VERSION 5.8 ;
BUSBITCHARS "[]" ;
DIVIDERCHAR "/" ;
UNITS
    DATABASE MICRONS 1000 ;
END UNITS

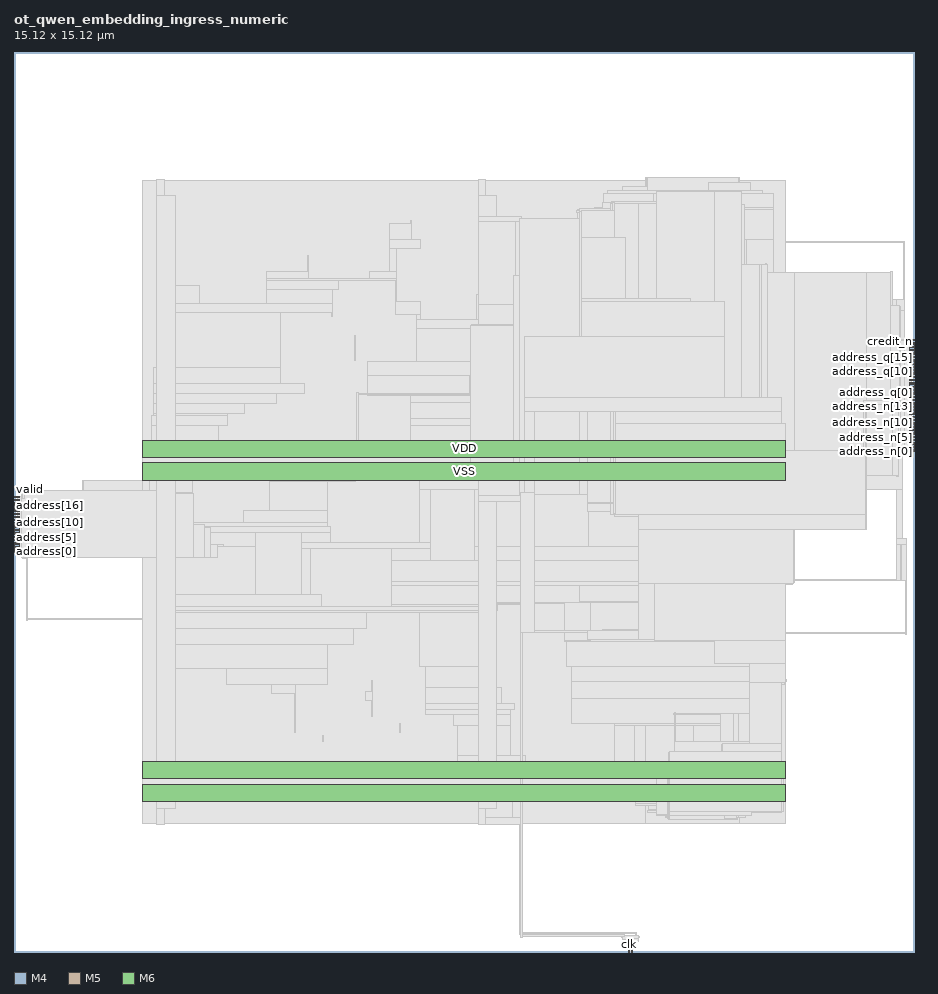
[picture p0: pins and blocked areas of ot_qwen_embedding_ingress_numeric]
MACRO ot_qwen_embedding_ingress_numeric
  FOREIGN ot_qwen_embedding_ingress_numeric 0 0 ;
  CLASS BLOCK ;
  SIZE 15.12 BY 15.12 ;
  PIN address[0]
    DIRECTION INPUT ;
    USE SIGNAL ;
    PORT
      LAYER M4 ;
        RECT  0 6.72 0.084 6.744 ;
    END
  END address[0]
  PIN address[10]
    DIRECTION INPUT ;
    USE SIGNAL ;
    PORT
      LAYER M4 ;
        RECT  0 7.2 0.084 7.224 ;
    END
  END address[10]
  PIN address[11]
    DIRECTION INPUT ;
    USE SIGNAL ;
    PORT
      LAYER M4 ;
        RECT  0 7.248 0.084 7.272 ;
    END
  END address[11]
  PIN address[12]
    DIRECTION INPUT ;
    USE SIGNAL ;
    PORT
      LAYER M4 ;
        RECT  0 7.296 0.084 7.32 ;
    END
  END address[12]
  PIN address[13]
    DIRECTION INPUT ;
    USE SIGNAL ;
    PORT
      LAYER M4 ;
        RECT  0 7.344 0.084 7.368 ;
    END
  END address[13]
  PIN address[14]
    DIRECTION INPUT ;
    USE SIGNAL ;
    PORT
      LAYER M4 ;
        RECT  0 7.392 0.084 7.416 ;
    END
  END address[14]
  PIN address[15]
    DIRECTION INPUT ;
    USE SIGNAL ;
    PORT
      LAYER M4 ;
        RECT  0 7.44 0.084 7.464 ;
    END
  END address[15]
  PIN address[16]
    DIRECTION INPUT ;
    USE SIGNAL ;
    PORT
      LAYER M4 ;
        RECT  0 7.488 0.084 7.512 ;
    END
  END address[16]
  PIN address[17]
    DIRECTION INPUT ;
    USE SIGNAL ;
    PORT
      LAYER M4 ;
        RECT  0 7.536 0.084 7.56 ;
    END
  END address[17]
  PIN address[1]
    DIRECTION INPUT ;
    USE SIGNAL ;
    PORT
      LAYER M4 ;
        RECT  0 6.768 0.084 6.792 ;
    END
  END address[1]
  PIN address[2]
    DIRECTION INPUT ;
    USE SIGNAL ;
    PORT
      LAYER M4 ;
        RECT  0 6.816 0.084 6.84 ;
    END
  END address[2]
  PIN address[3]
    DIRECTION INPUT ;
    USE SIGNAL ;
    PORT
      LAYER M4 ;
        RECT  0 6.864 0.084 6.888 ;
    END
  END address[3]
  PIN address[4]
    DIRECTION INPUT ;
    USE SIGNAL ;
    PORT
      LAYER M4 ;
        RECT  0 6.912 0.084 6.936 ;
    END
  END address[4]
  PIN address[5]
    DIRECTION INPUT ;
    USE SIGNAL ;
    PORT
      LAYER M4 ;
        RECT  0 6.96 0.084 6.984 ;
    END
  END address[5]
  PIN address[6]
    DIRECTION INPUT ;
    USE SIGNAL ;
    PORT
      LAYER M4 ;
        RECT  0 7.008 0.084 7.032 ;
    END
  END address[6]
  PIN address[7]
    DIRECTION INPUT ;
    USE SIGNAL ;
    PORT
      LAYER M4 ;
        RECT  0 7.056 0.084 7.08 ;
    END
  END address[7]
  PIN address[8]
    DIRECTION INPUT ;
    USE SIGNAL ;
    PORT
      LAYER M4 ;
        RECT  0 7.104 0.084 7.128 ;
    END
  END address[8]
  PIN address[9]
    DIRECTION INPUT ;
    USE SIGNAL ;
    PORT
      LAYER M4 ;
        RECT  0 7.152 0.084 7.176 ;
    END
  END address[9]
  PIN address_n[0]
    DIRECTION OUTPUT ;
    USE SIGNAL ;
    PORT
      LAYER M4 ;
        RECT  15.036 8.4 15.12 8.424 ;
    END
  END address_n[0]
  PIN address_n[10]
    DIRECTION OUTPUT ;
    USE SIGNAL ;
    PORT
      LAYER M4 ;
        RECT  15.036 8.88 15.12 8.904 ;
    END
  END address_n[10]
  PIN address_n[11]
    DIRECTION OUTPUT ;
    USE SIGNAL ;
    PORT
      LAYER M4 ;
        RECT  15.036 8.928 15.12 8.952 ;
    END
  END address_n[11]
  PIN address_n[12]
    DIRECTION OUTPUT ;
    USE SIGNAL ;
    PORT
      LAYER M4 ;
        RECT  15.036 8.976 15.12 9 ;
    END
  END address_n[12]
  PIN address_n[13]
    DIRECTION OUTPUT ;
    USE SIGNAL ;
    PORT
      LAYER M4 ;
        RECT  15.036 9.024 15.12 9.048 ;
    END
  END address_n[13]
  PIN address_n[14]
    DIRECTION OUTPUT ;
    USE SIGNAL ;
    PORT
      LAYER M4 ;
        RECT  15.036 9.072 15.12 9.096 ;
    END
  END address_n[14]
  PIN address_n[15]
    DIRECTION OUTPUT ;
    USE SIGNAL ;
    PORT
      LAYER M4 ;
        RECT  15.036 9.12 15.12 9.144 ;
    END
  END address_n[15]
  PIN address_n[16]
    DIRECTION OUTPUT ;
    USE SIGNAL ;
    PORT
      LAYER M4 ;
        RECT  15.036 9.168 15.12 9.192 ;
    END
  END address_n[16]
  PIN address_n[17]
    DIRECTION OUTPUT ;
    USE SIGNAL ;
    PORT
      LAYER M4 ;
        RECT  15.036 9.216 15.12 9.24 ;
    END
  END address_n[17]
  PIN address_n[1]
    DIRECTION OUTPUT ;
    USE SIGNAL ;
    PORT
      LAYER M4 ;
        RECT  15.036 8.448 15.12 8.472 ;
    END
  END address_n[1]
  PIN address_n[2]
    DIRECTION OUTPUT ;
    USE SIGNAL ;
    PORT
      LAYER M4 ;
        RECT  15.036 8.496 15.12 8.52 ;
    END
  END address_n[2]
  PIN address_n[3]
    DIRECTION OUTPUT ;
    USE SIGNAL ;
    PORT
      LAYER M4 ;
        RECT  15.036 8.544 15.12 8.568 ;
    END
  END address_n[3]
  PIN address_n[4]
    DIRECTION OUTPUT ;
    USE SIGNAL ;
    PORT
      LAYER M4 ;
        RECT  15.036 8.592 15.12 8.616 ;
    END
  END address_n[4]
  PIN address_n[5]
    DIRECTION OUTPUT ;
    USE SIGNAL ;
    PORT
      LAYER M4 ;
        RECT  15.036 8.64 15.12 8.664 ;
    END
  END address_n[5]
  PIN address_n[6]
    DIRECTION OUTPUT ;
    USE SIGNAL ;
    PORT
      LAYER M4 ;
        RECT  15.036 8.688 15.12 8.712 ;
    END
  END address_n[6]
  PIN address_n[7]
    DIRECTION OUTPUT ;
    USE SIGNAL ;
    PORT
      LAYER M4 ;
        RECT  15.036 8.736 15.12 8.76 ;
    END
  END address_n[7]
  PIN address_n[8]
    DIRECTION OUTPUT ;
    USE SIGNAL ;
    PORT
      LAYER M4 ;
        RECT  15.036 8.784 15.12 8.808 ;
    END
  END address_n[8]
  PIN address_n[9]
    DIRECTION OUTPUT ;
    USE SIGNAL ;
    PORT
      LAYER M4 ;
        RECT  15.036 8.832 15.12 8.856 ;
    END
  END address_n[9]
  PIN address_q[0]
    DIRECTION OUTPUT ;
    USE SIGNAL ;
    PORT
      LAYER M4 ;
        RECT  15.036 9.264 15.12 9.288 ;
    END
  END address_q[0]
  PIN address_q[10]
    DIRECTION OUTPUT ;
    USE SIGNAL ;
    PORT
      LAYER M4 ;
        RECT  15.036 9.744 15.12 9.768 ;
    END
  END address_q[10]
  PIN address_q[11]
    DIRECTION OUTPUT ;
    USE SIGNAL ;
    PORT
      LAYER M4 ;
        RECT  15.036 9.792 15.12 9.816 ;
    END
  END address_q[11]
  PIN address_q[12]
    DIRECTION OUTPUT ;
    USE SIGNAL ;
    PORT
      LAYER M4 ;
        RECT  15.036 9.84 15.12 9.864 ;
    END
  END address_q[12]
  PIN address_q[13]
    DIRECTION OUTPUT ;
    USE SIGNAL ;
    PORT
      LAYER M4 ;
        RECT  15.036 9.888 15.12 9.912 ;
    END
  END address_q[13]
  PIN address_q[14]
    DIRECTION OUTPUT ;
    USE SIGNAL ;
    PORT
      LAYER M4 ;
        RECT  15.036 9.936 15.12 9.96 ;
    END
  END address_q[14]
  PIN address_q[15]
    DIRECTION OUTPUT ;
    USE SIGNAL ;
    PORT
      LAYER M4 ;
        RECT  15.036 9.984 15.12 10.008 ;
    END
  END address_q[15]
  PIN address_q[16]
    DIRECTION OUTPUT ;
    USE SIGNAL ;
    PORT
      LAYER M4 ;
        RECT  15.036 10.032 15.12 10.056 ;
    END
  END address_q[16]
  PIN address_q[17]
    DIRECTION OUTPUT ;
    USE SIGNAL ;
    PORT
      LAYER M4 ;
        RECT  15.036 10.08 15.12 10.104 ;
    END
  END address_q[17]
  PIN address_q[1]
    DIRECTION OUTPUT ;
    USE SIGNAL ;
    PORT
      LAYER M4 ;
        RECT  15.036 9.312 15.12 9.336 ;
    END
  END address_q[1]
  PIN address_q[2]
    DIRECTION OUTPUT ;
    USE SIGNAL ;
    PORT
      LAYER M4 ;
        RECT  15.036 9.36 15.12 9.384 ;
    END
  END address_q[2]
  PIN address_q[3]
    DIRECTION OUTPUT ;
    USE SIGNAL ;
    PORT
      LAYER M4 ;
        RECT  15.036 9.408 15.12 9.432 ;
    END
  END address_q[3]
  PIN address_q[4]
    DIRECTION OUTPUT ;
    USE SIGNAL ;
    PORT
      LAYER M4 ;
        RECT  15.036 9.456 15.12 9.48 ;
    END
  END address_q[4]
  PIN address_q[5]
    DIRECTION OUTPUT ;
    USE SIGNAL ;
    PORT
      LAYER M4 ;
        RECT  15.036 9.504 15.12 9.528 ;
    END
  END address_q[5]
  PIN address_q[6]
    DIRECTION OUTPUT ;
    USE SIGNAL ;
    PORT
      LAYER M4 ;
        RECT  15.036 9.552 15.12 9.576 ;
    END
  END address_q[6]
  PIN address_q[7]
    DIRECTION OUTPUT ;
    USE SIGNAL ;
    PORT
      LAYER M4 ;
        RECT  15.036 9.6 15.12 9.624 ;
    END
  END address_q[7]
  PIN address_q[8]
    DIRECTION OUTPUT ;
    USE SIGNAL ;
    PORT
      LAYER M4 ;
        RECT  15.036 9.648 15.12 9.672 ;
    END
  END address_q[8]
  PIN address_q[9]
    DIRECTION OUTPUT ;
    USE SIGNAL ;
    PORT
      LAYER M4 ;
        RECT  15.036 9.696 15.12 9.72 ;
    END
  END address_q[9]
  PIN clk
    DIRECTION INPUT ;
    USE SIGNAL ;
    PORT
      LAYER M5 ;
        RECT  10.32 0 10.344 0.084 ;
    END
  END clk
  PIN credit
    DIRECTION INPUT ;
    USE SIGNAL ;
    PORT
      LAYER M4 ;
        RECT  0 7.584 0.084 7.608 ;
    END
  END credit
  PIN credit_n
    DIRECTION OUTPUT ;
    USE SIGNAL ;
    PORT
      LAYER M4 ;
        RECT  15.036 10.128 15.12 10.152 ;
    END
  END credit_n
  PIN credit_q
    DIRECTION OUTPUT ;
    USE SIGNAL ;
    PORT
      LAYER M4 ;
        RECT  15.036 10.176 15.12 10.2 ;
    END
  END credit_q
  PIN rst_n
    DIRECTION INPUT ;
    USE SIGNAL ;
    PORT
      LAYER M5 ;
        RECT  10.368 0 10.392 0.084 ;
    END
  END rst_n
  PIN valid
    DIRECTION INPUT ;
    USE SIGNAL ;
    PORT
      LAYER M4 ;
        RECT  0 7.632 0.084 7.656 ;
    END
  END valid
  PIN valid_n
    DIRECTION OUTPUT ;
    USE SIGNAL ;
    PORT
      LAYER M4 ;
        RECT  15.036 10.224 15.12 10.248 ;
    END
  END valid_n
  PIN valid_q
    DIRECTION OUTPUT ;
    USE SIGNAL ;
    PORT
      LAYER M4 ;
        RECT  15.036 10.272 15.12 10.296 ;
    END
  END valid_q
  PIN VDD
    DIRECTION INOUT ;
    USE POWER ;
    PORT
      LAYER M6 ;
        RECT  2.16 8.313 12.96 8.601 ;
        RECT  2.16 2.913 12.96 3.201 ;
    END
  END VDD
  PIN VSS
    DIRECTION INOUT ;
    USE GROUND ;
    PORT
      LAYER M6 ;
        RECT  2.16 7.929 12.96 8.217 ;
        RECT  2.16 2.529 12.96 2.817 ;
    END
  END VSS
  OBS
    LAYER RVTN ;
     RECT  2.16 2.16 12.96 2.295 ;
     RECT  2.16 2.565 12.96 2.835 ;
     RECT  2.16 3.105 12.96 3.375 ;
     RECT  2.16 3.645 12.96 3.915 ;
     RECT  2.16 4.185 12.96 4.455 ;
     RECT  2.16 4.725 12.96 4.995 ;
     RECT  2.16 5.265 12.96 5.535 ;
     RECT  2.16 5.805 12.96 6.075 ;
     RECT  2.16 6.345 12.96 6.615 ;
     RECT  2.16 6.885 12.96 7.155 ;
     RECT  2.16 7.425 12.96 7.695 ;
     RECT  2.16 7.965 12.96 8.235 ;
     RECT  2.16 8.505 12.96 8.775 ;
     RECT  2.16 9.045 12.96 9.315 ;
     RECT  2.16 9.585 12.96 9.855 ;
     RECT  2.16 10.125 12.96 10.395 ;
     RECT  2.16 10.665 12.96 10.935 ;
     RECT  2.16 11.205 12.96 11.475 ;
     RECT  2.16 11.745 12.96 12.015 ;
     RECT  2.16 12.285 12.96 12.555 ;
     RECT  2.16 12.825 12.96 12.96 ;
    LAYER RVTP ;
     RECT  2.16 2.295 12.96 2.565 ;
     RECT  2.16 2.835 12.96 3.105 ;
     RECT  2.16 3.375 12.96 3.645 ;
     RECT  2.16 3.915 12.96 4.185 ;
     RECT  2.16 4.455 12.96 4.725 ;
     RECT  2.16 4.995 12.96 5.265 ;
     RECT  2.16 5.535 12.96 5.805 ;
     RECT  2.16 6.075 12.96 6.345 ;
     RECT  2.16 6.615 12.96 6.885 ;
     RECT  2.16 7.155 12.96 7.425 ;
     RECT  2.16 7.695 12.96 7.965 ;
     RECT  2.16 8.235 12.96 8.505 ;
     RECT  2.16 8.775 12.96 9.045 ;
     RECT  2.16 9.315 12.96 9.585 ;
     RECT  2.16 9.855 12.96 10.125 ;
     RECT  2.16 10.395 12.96 10.665 ;
     RECT  2.16 10.935 12.96 11.205 ;
     RECT  2.16 11.475 12.96 11.745 ;
     RECT  2.16 12.015 12.96 12.285 ;
     RECT  2.16 12.555 12.96 12.825 ;
    LAYER M1 ;
     RECT  2.16 2.151 12.96 12.969 ;
    LAYER M2 ;
     RECT  0.139 6.894 1.147 7.416 ;
     RECT  0.211 5.58 2.16 5.598 ;
     RECT  1.147 6.894 2.16 7.92 ;
     RECT  8.491 0.306 10.463 0.324 ;
     RECT  2.16 2.151 10.615 12.969 ;
     RECT  10.615 2.151 12.191 13.014 ;
     RECT  12.191 2.151 12.96 12.969 ;
     RECT  12.96 8.856 13.091 11.124 ;
     RECT  13.091 9.126 13.667 11.124 ;
     RECT  13.667 9.126 14.243 10.962 ;
     RECT  12.96 7.776 14.279 7.794 ;
     RECT  14.243 9.126 14.315 9.684 ;
     RECT  12.96 6.246 14.827 6.264 ;
     RECT  14.243 10.44 14.855 10.962 ;
     RECT  14.827 6.246 14.899 6.876 ;
     RECT  14.899 6.246 14.927 6.948 ;
     RECT  14.855 10.44 14.927 10.458 ;
     RECT  14.315 9.126 14.963 9.144 ;
     RECT  12.96 11.916 14.963 11.934 ;
     RECT  12.96 5.346 14.999 5.364 ;
     RECT  14.927 6.93 14.999 6.948 ;
    LAYER M3 ;
     RECT  10.332 0.043 10.35 0.235 ;
     RECT  10.332 0.235 10.458 0.269 ;
     RECT  10.44 0.269 10.458 0.329 ;
     RECT  8.496 0.301 8.514 2.143 ;
     RECT  11.412 2.227 12.15 2.251 ;
     RECT  7.815 2.143 8.514 2.255 ;
     RECT  10.98 2.251 12.15 2.263 ;
     RECT  10.98 2.263 12.294 2.347 ;
     RECT  10.656 2.347 12.366 2.371 ;
     RECT  10.656 2.371 12.51 2.395 ;
     RECT  2.415 2.143 2.505 2.413 ;
     RECT  10.656 2.395 12.834 2.461 ;
     RECT  10.44 2.461 12.834 2.489 ;
     RECT  10.44 2.489 12.762 2.605 ;
     RECT  10.404 2.605 12.762 2.861 ;
     RECT  10.404 2.861 10.458 2.875 ;
     RECT  9.684 2.875 10.458 3.001 ;
     RECT  9.468 3.001 10.458 3.029 ;
     RECT  9.468 3.029 10.422 3.101 ;
     RECT  7.815 2.255 8.37 3.145 ;
     RECT  7.815 3.145 8.586 3.181 ;
     RECT  7.452 3.181 8.586 3.299 ;
     RECT  5.184 3.541 5.202 3.641 ;
     RECT  7.452 3.299 8.334 3.811 ;
     RECT  10.08 3.101 10.422 3.811 ;
     RECT  11.412 2.861 12.762 3.811 ;
     RECT  6.48 3.685 6.498 3.839 ;
     RECT  10.08 3.811 12.762 3.847 ;
     RECT  7.38 3.811 8.334 3.991 ;
     RECT  6.912 3.991 8.334 4.081 ;
     RECT  6.912 4.081 8.406 4.181 ;
     RECT  6.012 3.955 6.03 4.225 ;
     RECT  9.36 3.847 12.762 4.261 ;
     RECT  4.716 3.685 4.734 4.351 ;
     RECT  5.904 4.225 6.03 4.379 ;
     RECT  6.912 4.181 8.19 4.451 ;
     RECT  4.32 4.351 4.734 4.495 ;
     RECT  9.36 4.261 12.834 4.541 ;
     RECT  6.012 4.379 6.03 4.559 ;
     RECT  2.415 2.413 2.697 4.765 ;
     RECT  3.564 4.495 5.274 4.765 ;
     RECT  6.912 4.451 8.097 4.801 ;
     RECT  9.36 4.541 12.726 4.801 ;
     RECT  2.415 4.765 5.274 5.161 ;
     RECT  9.288 4.801 12.726 5.224 ;
     RECT  9.252 5.224 12.726 5.261 ;
     RECT  2.415 5.161 5.706 5.431 ;
     RECT  2.415 5.431 5.922 5.701 ;
     RECT  6.804 4.801 8.097 5.701 ;
     RECT  2.415 5.701 8.097 5.737 ;
     RECT  2.415 5.737 8.118 5.801 ;
     RECT  6.336 5.801 8.118 5.845 ;
     RECT  9.504 5.261 12.726 5.845 ;
     RECT  9.504 5.845 12.762 5.881 ;
     RECT  2.415 5.801 5.166 5.999 ;
     RECT  6.336 5.845 8.73 6.151 ;
     RECT  9.504 5.881 12.834 6.151 ;
     RECT  6.336 6.151 12.834 6.221 ;
     RECT  14.976 5.341 14.994 6.241 ;
     RECT  6.336 6.221 12.762 6.575 ;
     RECT  0.216 5.575 0.234 6.619 ;
     RECT  4.824 5.999 4.986 6.781 ;
     RECT  6.336 6.575 7.002 6.781 ;
     RECT  7.74 6.575 12.762 6.809 ;
     RECT  2.415 5.999 4.05 6.817 ;
     RECT  14.904 6.241 14.994 6.853 ;
     RECT  0.144 6.619 0.234 6.859 ;
     RECT  4.824 6.781 7.002 6.881 ;
     RECT  0.144 6.859 0.342 6.907 ;
     RECT  14.832 6.853 14.994 6.953 ;
     RECT  0.144 6.907 0.414 7.037 ;
     RECT  2.304 6.817 4.05 7.051 ;
     RECT  4.824 6.881 5.31 7.051 ;
     RECT  2.304 7.051 5.31 7.151 ;
     RECT  2.304 7.151 5.274 7.223 ;
     RECT  1.152 7.195 1.17 7.243 ;
     RECT  1.152 7.243 1.242 7.385 ;
     RECT  0.144 7.037 0.342 7.421 ;
     RECT  3.852 7.223 5.274 7.421 ;
     RECT  0.216 7.421 0.342 7.661 ;
     RECT  0.216 7.661 0.234 7.709 ;
     RECT  2.304 7.223 3.006 7.723 ;
     RECT  6.804 6.881 7.002 7.771 ;
     RECT  7.74 6.809 8.73 7.771 ;
     RECT  9.648 6.809 12.762 7.771 ;
     RECT  14.832 6.953 14.922 7.771 ;
     RECT  4.284 7.421 5.274 7.897 ;
     RECT  1.152 7.385 1.17 7.925 ;
     RECT  6.804 7.771 12.762 7.933 ;
     RECT  4.284 7.897 5.742 7.961 ;
     RECT  6.624 7.933 12.834 7.997 ;
     RECT  4.5 7.961 5.742 8.041 ;
     RECT  6.624 7.997 12.762 8.041 ;
     RECT  2.268 7.723 3.006 8.131 ;
     RECT  2.268 8.131 3.222 8.195 ;
     RECT  4.5 8.041 12.762 8.195 ;
     RECT  5.04 8.195 12.762 8.231 ;
     RECT  2.304 8.195 3.222 8.311 ;
     RECT  5.724 8.231 12.762 8.429 ;
     RECT  6.48 8.429 12.762 8.465 ;
     RECT  5.724 8.429 5.742 8.477 ;
     RECT  2.304 8.311 3.438 8.851 ;
     RECT  6.66 8.465 12.762 8.851 ;
     RECT  6.66 8.851 13.086 8.957 ;
     RECT  14.256 7.771 14.922 8.971 ;
     RECT  2.304 8.851 3.582 9.005 ;
     RECT  2.34 9.005 3.582 9.049 ;
     RECT  14.256 8.971 14.958 9.163 ;
     RECT  2.34 9.049 3.87 9.211 ;
     RECT  6.66 8.957 12.834 9.239 ;
     RECT  6.66 9.239 12.762 9.355 ;
     RECT  2.34 9.211 4.41 9.391 ;
     RECT  2.34 9.391 4.878 9.545 ;
     RECT  5.94 9.355 12.762 9.689 ;
     RECT  2.34 9.545 4.482 9.815 ;
     RECT  5.94 9.689 8.097 9.923 ;
     RECT  8.928 9.689 12.762 10.085 ;
     RECT  5.724 9.931 5.742 10.355 ;
     RECT  6.768 9.923 8.097 10.471 ;
     RECT  8.928 10.085 12.69 10.471 ;
     RECT  6.768 10.471 12.69 10.625 ;
     RECT  6.768 10.625 6.822 10.705 ;
     RECT  2.415 9.815 4.482 10.741 ;
     RECT  5.328 10.669 5.346 10.741 ;
     RECT  13.644 9.163 14.958 10.769 ;
     RECT  2.415 10.741 5.346 10.895 ;
     RECT  6.408 10.705 6.822 10.931 ;
     RECT  14.832 10.769 14.958 10.967 ;
     RECT  7.776 10.625 12.69 11.039 ;
     RECT  13.644 10.769 13.662 11.129 ;
     RECT  4.248 10.895 5.346 11.137 ;
     RECT  2.415 10.895 3.114 11.201 ;
     RECT  7.815 11.039 12.69 11.245 ;
     RECT  4.248 11.137 5.454 11.281 ;
     RECT  6.408 10.931 6.426 11.281 ;
     RECT  4.248 11.281 6.426 11.309 ;
     RECT  4.248 11.309 4.95 11.435 ;
     RECT  5.976 11.309 6.426 11.435 ;
     RECT  4.932 11.435 4.95 11.705 ;
     RECT  6.3 11.435 6.426 11.821 ;
     RECT  14.94 10.967 14.958 11.939 ;
     RECT  6.3 11.821 6.822 11.975 ;
     RECT  7.815 11.245 12.762 11.975 ;
     RECT  7.815 11.975 8.478 12.083 ;
     RECT  6.3 11.975 6.678 12.245 ;
     RECT  6.66 12.245 6.678 12.281 ;
     RECT  9.468 11.975 12.762 12.479 ;
     RECT  9.756 12.479 12.762 12.515 ;
     RECT  2.415 11.201 2.697 12.707 ;
     RECT  7.815 12.083 8.097 12.707 ;
     RECT  9.9 12.515 12.762 12.749 ;
     RECT  9.972 12.749 12.582 12.785 ;
     RECT  10.224 12.785 10.638 12.857 ;
     RECT  11.664 12.785 12.366 12.929 ;
     RECT  2.415 12.707 2.505 12.977 ;
     RECT  7.815 12.707 7.905 12.977 ;
     RECT  10.62 12.857 10.638 13.019 ;
     RECT  12.168 12.929 12.186 13.019 ;
    LAYER M4 ;
     RECT  0.06 6.72 0.133 7.656 ;
     RECT  0.133 6.624 2.408 7.752 ;
     RECT  2.408 2.148 2.512 12.972 ;
     RECT  2.512 2.418 2.704 12.702 ;
     RECT  2.704 6.624 3.017 7.704 ;
     RECT  3.017 6.624 3.197 7.176 ;
     RECT  3.197 6.624 3.305 7.128 ;
     RECT  3.305 6.624 3.413 6.84 ;
     RECT  3.413 6.816 3.521 6.84 ;
     RECT  5.708 8.448 5.749 8.472 ;
     RECT  5.749 8.448 5.795 9.384 ;
     RECT  5.795 9.36 7.649 9.384 ;
     RECT  7.649 9.36 7.669 9.672 ;
     RECT  7.669 9.36 7.808 10.488 ;
     RECT  7.808 2.148 7.912 12.972 ;
     RECT  7.912 2.418 8.104 12.702 ;
     RECT  8.104 10.848 8.531 12.312 ;
     RECT  8.104 7.584 8.561 8.472 ;
     RECT  8.531 10.848 8.597 11.448 ;
     RECT  8.561 7.68 8.668 8.472 ;
     RECT  8.668 7.968 8.819 8.472 ;
     RECT  8.104 5.856 9.241 5.88 ;
     RECT  8.104 9.648 9.385 9.672 ;
     RECT  9.385 9.648 9.457 9.816 ;
     RECT  8.819 7.968 9.637 8.088 ;
     RECT  9.457 9.504 9.644 9.816 ;
     RECT  8.597 11.424 9.673 11.448 ;
     RECT  9.452 12.432 9.673 12.456 ;
     RECT  9.241 5.232 9.683 5.88 ;
     RECT  9.644 9.072 9.685 9.816 ;
     RECT  9.685 9.072 9.733 10.344 ;
     RECT  9.673 11.424 9.733 12.456 ;
     RECT  9.733 9.072 9.889 12.456 ;
     RECT  9.637 7.392 10.028 8.088 ;
     RECT  10.028 7.344 10.117 8.088 ;
     RECT  9.889 9.072 10.117 12.6 ;
     RECT  10.117 7.344 10.259 12.6 ;
     RECT  10.213 0.24 10.277 0.264 ;
     RECT  10.277 0.048 10.361 0.264 ;
     RECT  9.683 5.376 10.501 5.88 ;
     RECT  10.259 7.344 10.501 8.472 ;
     RECT  10.361 0.24 10.513 0.264 ;
     RECT  10.259 9.648 10.748 12.6 ;
     RECT  10.748 9.648 10.835 12.744 ;
     RECT  10.645 2.352 10.861 2.376 ;
     RECT  10.501 5.376 10.924 8.472 ;
     RECT  10.861 2.352 10.94 2.424 ;
     RECT  10.94 2.256 10.969 2.424 ;
     RECT  10.924 8.064 10.979 8.472 ;
     RECT  10.969 2.256 11.027 2.76 ;
     RECT  11.027 2.4 11.077 2.76 ;
     RECT  10.979 8.064 11.081 8.184 ;
     RECT  10.835 9.648 11.413 11.976 ;
     RECT  11.413 9.168 11.621 11.976 ;
     RECT  11.077 2.4 11.861 2.856 ;
     RECT  11.077 3.984 11.861 4.008 ;
     RECT  10.924 5.376 11.861 7.08 ;
     RECT  11.861 5.088 11.989 7.08 ;
     RECT  11.861 2.4 12.085 4.008 ;
     RECT  12.085 2.256 12.172 4.008 ;
     RECT  11.621 9.264 12.181 11.976 ;
     RECT  12.181 9.264 12.269 12.552 ;
     RECT  12.269 9.264 12.305 11.976 ;
     RECT  12.172 2.352 12.377 4.008 ;
     RECT  12.377 2.4 12.515 4.008 ;
     RECT  11.989 5.088 12.521 7.848 ;
     RECT  12.515 3.936 12.563 4.008 ;
     RECT  12.305 9.264 12.601 11.448 ;
     RECT  12.601 9.264 12.637 11.4 ;
     RECT  12.565 4.512 12.652 4.872 ;
     RECT  12.515 2.4 12.701 2.904 ;
     RECT  12.637 10.8 12.701 11.4 ;
     RECT  12.521 6.192 12.773 7.848 ;
     RECT  12.637 9.264 12.805 9.672 ;
     RECT  12.701 2.4 12.899 2.424 ;
     RECT  12.652 4.512 12.947 4.536 ;
     RECT  12.805 7.968 13.043 7.992 ;
     RECT  12.805 9.168 13.057 9.672 ;
     RECT  12.773 6.192 13.091 6.216 ;
     RECT  13.057 8.928 13.669 9.672 ;
     RECT  13.669 8.928 14.197 9.72 ;
     RECT  14.197 8.736 14.209 9.72 ;
     RECT  14.209 8.736 14.245 10.008 ;
     RECT  14.245 8.544 14.293 10.152 ;
     RECT  14.293 8.544 14.725 10.296 ;
     RECT  14.725 8.496 14.821 10.296 ;
     RECT  14.821 8.448 14.917 10.296 ;
     RECT  14.917 8.4 15.084 10.296 ;
    LAYER M5 ;
     RECT  10.32 0.016 10.392 0.181 ;
     RECT  10.32 0.181 10.488 0.211 ;
     RECT  10.224 0.211 10.488 0.275 ;
     RECT  10.224 0.275 10.248 0.299 ;
     RECT  10.992 2.229 11.016 2.293 ;
     RECT  12.096 2.229 12.12 2.293 ;
     RECT  10.8 2.293 11.016 2.351 ;
     RECT  12.096 2.293 12.36 2.351 ;
     RECT  10.8 2.351 12.888 2.387 ;
     RECT  2.4 2.137 2.52 2.407 ;
     RECT  7.8 2.137 7.92 2.407 ;
     RECT  11.088 2.387 12.888 2.435 ;
     RECT  11.088 2.435 12.504 3.539 ;
     RECT  12.528 3.925 12.552 4.011 ;
     RECT  11.088 3.539 11.112 4.019 ;
     RECT  12.576 4.501 12.936 4.587 ;
     RECT  12.576 4.587 12.6 4.907 ;
     RECT  9.648 5.221 9.672 5.305 ;
     RECT  9.888 5.331 9.912 5.365 ;
     RECT  9.888 5.365 10.872 5.419 ;
     RECT  10.848 5.419 10.872 5.605 ;
     RECT  11.904 5.039 12.504 5.605 ;
     RECT  10.848 5.605 12.504 5.877 ;
     RECT  10.848 5.877 12.552 6.181 ;
     RECT  10.848 6.181 13.08 6.265 ;
     RECT  10.848 6.265 12.552 6.739 ;
     RECT  10.752 6.739 12.552 6.767 ;
     RECT  10.56 6.767 12.552 7.147 ;
     RECT  12 7.147 12.552 7.187 ;
     RECT  10.56 7.147 10.872 7.315 ;
     RECT  10.08 7.315 10.872 7.541 ;
     RECT  7.8 2.407 8.112 7.573 ;
     RECT  7.8 7.573 8.52 7.669 ;
     RECT  0.144 7.621 0.168 7.763 ;
     RECT  12 7.187 12.024 7.859 ;
     RECT  9.648 7.541 10.872 8.003 ;
     RECT  14.832 7.989 14.856 8.053 ;
     RECT  14.736 8.053 14.856 8.373 ;
     RECT  7.8 7.669 8.616 8.437 ;
     RECT  10.128 8.003 10.872 8.437 ;
     RECT  14.736 8.373 14.952 8.533 ;
     RECT  13.008 7.413 13.176 8.619 ;
     RECT  14.256 8.533 14.952 8.725 ;
     RECT  10.128 8.437 10.968 8.811 ;
     RECT  14.208 8.725 14.952 8.811 ;
     RECT  13.008 8.619 13.08 8.939 ;
     RECT  7.8 8.437 8.808 9.043 ;
     RECT  10.128 8.811 10.248 9.043 ;
     RECT  7.8 9.043 10.248 9.145 ;
     RECT  13.056 8.939 13.08 9.203 ;
     RECT  5.76 8.437 5.784 9.395 ;
     RECT  11.328 9.119 11.448 9.493 ;
     RECT  7.8 9.145 10.152 9.619 ;
     RECT  7.68 9.619 10.152 9.707 ;
     RECT  11.328 9.493 11.976 9.779 ;
     RECT  9.648 9.707 10.152 9.865 ;
     RECT  11.808 9.779 11.976 10.101 ;
     RECT  14.256 8.811 14.952 10.163 ;
     RECT  11.808 10.101 12.456 10.213 ;
     RECT  9.696 9.865 10.152 10.261 ;
     RECT  14.304 10.163 14.952 10.283 ;
     RECT  14.304 10.283 14.328 10.307 ;
     RECT  9.696 10.261 10.728 10.355 ;
     RECT  7.68 9.707 8.568 10.539 ;
     RECT  11.808 10.213 12.552 10.549 ;
     RECT  9.744 10.355 10.728 10.805 ;
     RECT  11.808 10.549 12.6 10.805 ;
     RECT  7.8 10.539 8.568 10.883 ;
     RECT  9.744 10.805 12.6 10.893 ;
     RECT  10.704 10.893 12.6 11.365 ;
     RECT  10.704 11.365 12.648 11.459 ;
     RECT  10.704 11.459 11.304 11.563 ;
     RECT  12.624 11.459 12.648 11.563 ;
     RECT  10.704 11.563 11.064 11.951 ;
     RECT  7.8 10.883 8.424 12.277 ;
     RECT  10.224 11.951 11.064 12.331 ;
     RECT  7.8 12.277 8.52 12.361 ;
     RECT  10.224 12.331 10.824 12.405 ;
     RECT  9.504 12.405 10.824 12.493 ;
     RECT  10.032 12.493 10.824 12.611 ;
     RECT  2.4 2.407 2.712 12.713 ;
     RECT  7.8 12.361 8.112 12.713 ;
     RECT  12.192 12.517 12.216 12.779 ;
     RECT  10.8 12.611 10.824 12.793 ;
     RECT  2.4 12.713 2.52 12.983 ;
     RECT  7.8 12.713 7.92 12.983 ;
    LAYER M6 ;
     RECT  2.16 7.929 7.669 8.601 ;
     RECT  7.669 7.929 8.389 10.528 ;
     RECT  8.389 7.929 8.485 11.36 ;
     RECT  8.485 7.68 9.493 12.32 ;
     RECT  8.693 5.376 9.637 5.408 ;
     RECT  9.493 7.68 9.637 12.448 ;
     RECT  9.637 7.552 10.021 12.448 ;
     RECT  10.021 7.552 10.069 12.576 ;
     RECT  8.501 0.256 10.259 0.288 ;
     RECT  9.637 5.248 10.485 5.408 ;
     RECT  10.069 7.36 10.485 12.576 ;
     RECT  10.357 0.192 10.499 0.224 ;
     RECT  2.16 2.529 10.789 3.201 ;
     RECT  10.485 5.248 10.789 12.576 ;
     RECT  10.789 2.304 10.981 3.201 ;
     RECT  10.981 2.24 10.997 3.201 ;
     RECT  10.789 5.248 11.765 12.768 ;
     RECT  10.997 2.24 11.893 3.36 ;
     RECT  11.893 2.24 12.131 3.488 ;
     RECT  11.765 4.864 12.227 12.768 ;
     RECT  12.131 2.304 12.395 3.488 ;
     RECT  12.395 2.368 12.517 3.488 ;
     RECT  12.227 4.864 12.517 11.552 ;
     RECT  12.517 2.368 12.563 11.552 ;
     RECT  12.563 2.368 12.611 4.896 ;
     RECT  12.563 6.208 12.659 11.552 ;
     RECT  12.611 2.368 12.843 4.576 ;
     RECT  12.843 2.368 12.922 3.201 ;
     RECT  12.922 2.529 12.96 3.201 ;
     RECT  12.843 4.544 12.971 4.576 ;
     RECT  12.659 6.208 13.114 11.424 ;
     RECT  13.114 7.104 14.315 11.424 ;
     RECT  14.315 8 14.763 11.424 ;
     RECT  14.763 8 14.867 10.848 ;
     RECT  14.867 8.384 14.891 10.848 ;
     RECT  14.891 8.384 14.963 10.272 ;
    LAYER M7 ;
     RECT  11.008 2.229 11.936 2.293 ;
     RECT  11.008 2.293 12.384 2.357 ;
     RECT  11.008 2.357 12.896 3.371 ;
     RECT  11.904 3.371 12.896 3.499 ;
     RECT  12.352 3.499 12.896 4.533 ;
     RECT  12.352 4.533 12.96 4.853 ;
     RECT  11.776 4.853 12.96 5.237 ;
     RECT  8.512 0.245 8.544 5.365 ;
     RECT  10.752 5.237 12.96 6.197 ;
     RECT  10.496 6.197 13.088 7.093 ;
     RECT  10.496 7.093 14.304 7.349 ;
     RECT  8.512 5.365 8.736 7.723 ;
     RECT  10.112 7.349 14.304 8.427 ;
     RECT  10.112 8.427 12.96 8.875 ;
     RECT  8.576 7.723 8.736 9.077 ;
     RECT  10.112 8.875 12.896 9.077 ;
     RECT  14.272 8.427 14.304 9.205 ;
     RECT  14.272 9.205 14.88 9.259 ;
     RECT  8.576 9.077 12.896 9.323 ;
     RECT  8.576 9.323 11.936 10.347 ;
     RECT  14.72 9.259 14.88 10.859 ;
     RECT  9.536 10.347 11.936 10.923 ;
     RECT  9.536 10.923 11.36 10.987 ;
     RECT  14.72 10.859 14.752 11.435 ;
     RECT  9.536 10.987 10.272 12.011 ;
     RECT  9.536 12.011 10.08 12.459 ;
     RECT  10.048 12.459 10.08 12.587 ;
  END
END ot_qwen_embedding_ingress_numeric
END LIBRARY
